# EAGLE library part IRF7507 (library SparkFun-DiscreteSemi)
Dual transistor NMOS/PMOS in one package.

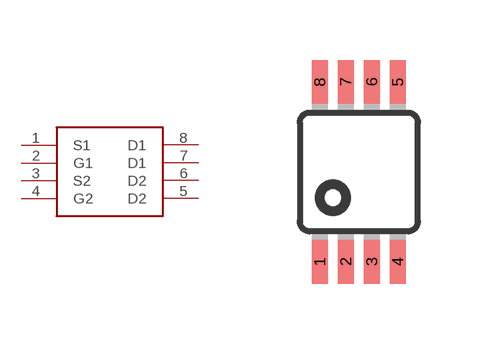
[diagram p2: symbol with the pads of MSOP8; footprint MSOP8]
Designator prefix -

## IRF7507  [MSOP8]
1  S1
2  G1
3  S2
4  G2
5  D2
6  D2
7  D1
8  D1

## Footprint MSOP8 (pad centres in mm)
8M, 8-Lead, 0.118" Wide, Miniature Small Outline Package MSOP 8M-Package doc1097.pdf
smd 0.4 x 1.1: 1 -0.975,-2.25; 2 -0.325,-2.25; 3 0.325,-2.25; 4 0.975,-2.25; 5 0.975,2.25; 6 0.325,2.25; 7 -0.325,2.25; 8 -0.975,2.25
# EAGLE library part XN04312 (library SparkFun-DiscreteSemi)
NPN/PNP Transistor Array Handy dandy transistor array for level shifting and inverting signals. Spark Fun Electronics SKU : COM-00588

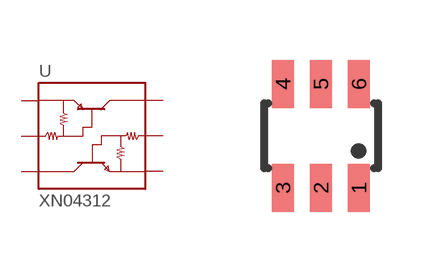
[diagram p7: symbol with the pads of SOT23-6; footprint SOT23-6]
Designator prefix -

## XN04312SOT  [SOT23-6]
1  C1
2  B2
3  E2
4  C2
5  B1
6  E1

## Footprint SOT23-6 (pad centres in mm)
smd 0.55 x 1.2: 1 0.95,-1.3; 2 0,-1.3; 3 -0.95,-1.3; 4 -0.95,1.3; 5 0,1.3; 6 0.95,1.3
